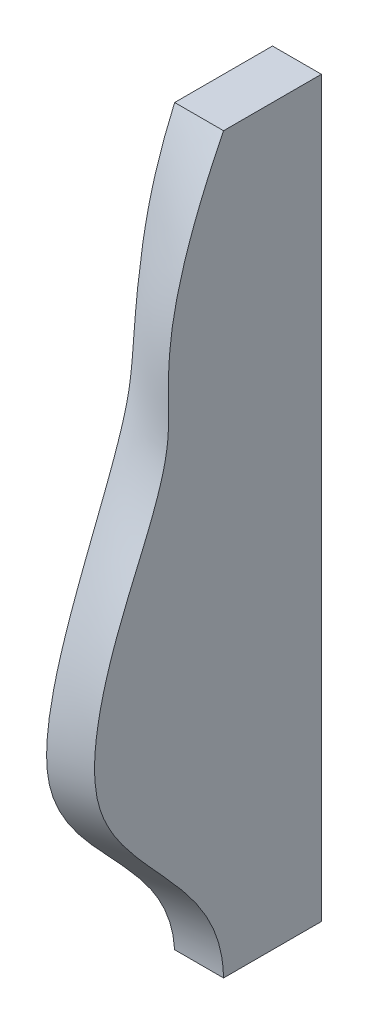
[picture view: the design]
ISO-10303-21;
HEADER;
FILE_DESCRIPTION(('STEP AP214'),'2;1');
FILE_NAME('part.step','',(''),(''),'','','');
FILE_SCHEMA(('AUTOMOTIVE_DESIGN { 1 0 10303 214 1 1 1 1 }'));
ENDSEC;
DATA;
#1=APPLICATION_CONTEXT('core data for automotive mechanical design processes');
#2=APPLICATION_PROTOCOL_DEFINITION('international standard','automotive_design',2000,#1);
#3=PRODUCT_CONTEXT('',#1,'mechanical');
#4=PRODUCT('Part','Part','',(#3));
#5=PRODUCT_RELATED_PRODUCT_CATEGORY('part','',(#4));
#6=PRODUCT_DEFINITION_FORMATION('','',#4);
#7=PRODUCT_DEFINITION_CONTEXT('part definition',#1,'design');
#8=PRODUCT_DEFINITION('design','',#6,#7);
#9=PRODUCT_DEFINITION_SHAPE('','',#8);
#10=(LENGTH_UNIT() NAMED_UNIT(*) SI_UNIT(.MILLI.,.METRE.));
#11=(NAMED_UNIT(*) PLANE_ANGLE_UNIT() SI_UNIT($,.RADIAN.));
#12=(NAMED_UNIT(*) SI_UNIT($,.STERADIAN.) SOLID_ANGLE_UNIT());
#13=UNCERTAINTY_MEASURE_WITH_UNIT(LENGTH_MEASURE(1.E-05),#10,'distance_accuracy_value','');
#14=(GEOMETRIC_REPRESENTATION_CONTEXT(3) GLOBAL_UNCERTAINTY_ASSIGNED_CONTEXT((#13)) GLOBAL_UNIT_ASSIGNED_CONTEXT((#10,
#11,#12)) REPRESENTATION_CONTEXT('',''));
#15=CARTESIAN_POINT('',(0.,0.,0.));
#16=DIRECTION('',(0.,0.,1.));
#17=DIRECTION('',(1.,0.,0.));
#18=AXIS2_PLACEMENT_3D('',#15,#16,#17);
#19=CARTESIAN_POINT('',(49.9999999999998,375.,253.120113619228));
#20=DIRECTION('',(1.,0.,0.));
#21=DIRECTION('',(0.,0.,-1.));
#22=AXIS2_PLACEMENT_3D('',#19,#20,#21);
#23=PLANE('',#22);
#24=CARTESIAN_POINT('',(49.9999999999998,375.,100.));
#25=CARTESIAN_POINT('',(49.9999999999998,373.168622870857,100.916189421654));
#26=CARTESIAN_POINT('',(49.9999999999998,371.334089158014,101.826077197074));
#27=CARTESIAN_POINT('',(49.9999999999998,367.660247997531,103.631973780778));
#28=CARTESIAN_POINT('',(49.9999999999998,365.820946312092,104.527994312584));
#29=CARTESIAN_POINT('',(49.9999999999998,362.137168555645,106.305876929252));
#30=CARTESIAN_POINT('',(49.9999999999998,360.292697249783,107.187748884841));
#31=CARTESIAN_POINT('',(49.9999999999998,356.598172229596,108.937033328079));
#32=CARTESIAN_POINT('',(49.9999999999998,354.748122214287,109.804453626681));
#33=CARTESIAN_POINT('',(49.9999999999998,351.042022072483,111.524514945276));
#34=CARTESIAN_POINT('',(49.9999999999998,349.185974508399,112.377161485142));
#35=CARTESIAN_POINT('',(49.9999999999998,345.467450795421,114.067332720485));
#36=CARTESIAN_POINT('',(49.9999999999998,343.604975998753,114.90486039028));
#37=CARTESIAN_POINT('',(49.9999999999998,339.897581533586,116.553563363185));
#38=CARTESIAN_POINT('',(49.9999999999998,338.052751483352,117.364940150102));
#39=CARTESIAN_POINT('',(49.9999999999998,334.35598507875,118.972212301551));
#40=CARTESIAN_POINT('',(49.9999999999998,332.504047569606,119.768105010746));
#41=CARTESIAN_POINT('',(49.9999999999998,328.792640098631,121.343978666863));
#42=CARTESIAN_POINT('',(49.9999999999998,326.933167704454,122.123953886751));
#43=CARTESIAN_POINT('',(49.9999999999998,323.206246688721,123.667520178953));
#44=CARTESIAN_POINT('',(49.9999999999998,321.338794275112,124.431102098));
#45=CARTESIAN_POINT('',(49.9999999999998,317.595448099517,125.941358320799));
#46=CARTESIAN_POINT('',(49.9999999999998,315.719549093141,126.68801962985));
#47=CARTESIAN_POINT('',(49.9999999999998,311.958818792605,128.163848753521));
#48=CARTESIAN_POINT('',(49.9999999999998,310.073980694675,128.892999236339));
#49=CARTESIAN_POINT('',(49.9999999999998,306.265596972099,130.34429258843));
#50=CARTESIAN_POINT('',(49.9999999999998,304.341929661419,131.066116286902));
#51=CARTESIAN_POINT('',(49.9999999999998,300.487016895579,132.489233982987));
#52=CARTESIAN_POINT('',(49.9999999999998,298.555771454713,133.190528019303));
#53=CARTESIAN_POINT('',(49.9999999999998,294.68424987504,134.572072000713));
#54=CARTESIAN_POINT('',(49.9999999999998,292.743968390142,135.252306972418));
#55=CARTESIAN_POINT('',(49.9999999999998,288.855617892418,136.590091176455));
#56=CARTESIAN_POINT('',(49.9999999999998,286.907548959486,137.247640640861));
#57=CARTESIAN_POINT('',(49.9999999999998,283.004365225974,138.538494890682));
#58=CARTESIAN_POINT('',(49.9999999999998,281.049254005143,139.171810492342));
#59=CARTESIAN_POINT('',(49.9999999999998,277.130982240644,140.413056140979));
#60=CARTESIAN_POINT('',(49.9999999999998,275.167821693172,141.020986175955));
#61=CARTESIAN_POINT('',(49.9999999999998,271.236123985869,142.208965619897));
#62=CARTESIAN_POINT('',(49.9999999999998,269.267598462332,142.789053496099));
#63=CARTESIAN_POINT('',(49.9999999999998,265.322260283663,143.920345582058));
#64=CARTESIAN_POINT('',(49.9999999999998,263.345447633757,144.471549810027));
#65=CARTESIAN_POINT('',(49.9999999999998,259.387696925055,145.542028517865));
#66=CARTESIAN_POINT('',(49.9999999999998,257.406776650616,146.061368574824));
#67=CARTESIAN_POINT('',(49.9999999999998,253.43672394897,147.067501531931));
#68=CARTESIAN_POINT('',(49.9999999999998,251.447591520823,147.554294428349));
#69=CARTESIAN_POINT('',(49.9999999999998,245.477945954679,148.960509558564));
#70=CARTESIAN_POINT('',(49.9999999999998,241.485046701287,149.828529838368));
#71=CARTESIAN_POINT('',(49.9999999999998,236.124367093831,150.88686863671));
#72=CARTESIAN_POINT('',(49.9999999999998,234.769759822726,151.145219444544));
#73=CARTESIAN_POINT('',(49.9999999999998,232.057202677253,151.643861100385));
#74=CARTESIAN_POINT('',(49.9999999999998,230.699252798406,151.884151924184));
#75=CARTESIAN_POINT('',(49.9999999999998,227.980192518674,152.346116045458));
#76=CARTESIAN_POINT('',(49.9999999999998,226.619082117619,152.567789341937));
#77=CARTESIAN_POINT('',(49.9999999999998,223.893831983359,152.992033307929));
#78=CARTESIAN_POINT('',(49.9999999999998,222.529692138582,153.194603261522));
#79=CARTESIAN_POINT('',(49.9999999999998,219.798652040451,153.580213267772));
#80=CARTESIAN_POINT('',(49.9999999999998,218.431751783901,153.763253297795));
#81=CARTESIAN_POINT('',(49.9999999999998,215.695441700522,154.109488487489));
#82=CARTESIAN_POINT('',(49.9999999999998,214.326031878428,154.272683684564));
#83=CARTESIAN_POINT('',(49.9999999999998,211.583465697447,154.579216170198));
#84=CARTESIAN_POINT('',(49.9999999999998,210.210306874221,154.72253141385));
#85=CARTESIAN_POINT('',(49.9999999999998,207.462038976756,154.989075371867));
#86=CARTESIAN_POINT('',(49.9999999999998,206.086929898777,155.112304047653));
#87=CARTESIAN_POINT('',(49.9999999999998,203.335080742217,155.338860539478));
#88=CARTESIAN_POINT('',(49.9999999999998,201.958340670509,155.44218843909));
#89=CARTESIAN_POINT('',(49.9999999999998,199.200402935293,155.629584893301));
#90=CARTESIAN_POINT('',(49.9999999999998,197.819202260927,155.713609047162));
#91=CARTESIAN_POINT('',(49.9999999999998,195.055784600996,155.862810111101));
#92=CARTESIAN_POINT('',(49.9999999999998,193.673567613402,155.927986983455));
#93=CARTESIAN_POINT('',(49.9999999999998,190.908421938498,156.040530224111));
#94=CARTESIAN_POINT('',(49.9999999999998,189.525493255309,156.087896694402));
#95=CARTESIAN_POINT('',(49.9999999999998,186.755163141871,156.166330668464));
#96=CARTESIAN_POINT('',(49.9999999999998,185.36776037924,156.197350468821));
#97=CARTESIAN_POINT('',(49.9999999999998,182.592709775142,156.244687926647));
#98=CARTESIAN_POINT('',(49.9999999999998,181.20506193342,156.261005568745));
#99=CARTESIAN_POINT('',(49.9999999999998,178.42968430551,156.281166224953));
#100=CARTESIAN_POINT('',(49.9999999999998,177.041954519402,156.285009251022));
#101=CARTESIAN_POINT('',(49.9999999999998,174.263514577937,156.282881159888));
#102=CARTESIAN_POINT('',(49.9999999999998,172.872804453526,156.276888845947));
#103=CARTESIAN_POINT('',(49.9999999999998,170.091440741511,156.258168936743));
#104=CARTESIAN_POINT('',(49.9999999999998,168.700787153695,156.24544136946));
#105=CARTESIAN_POINT('',(49.9999999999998,165.919509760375,156.21679163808));
#106=CARTESIAN_POINT('',(49.9999999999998,164.528885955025,156.200869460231));
#107=CARTESIAN_POINT('',(49.9999999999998,161.828743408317,156.170666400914));
#108=CARTESIAN_POINT('',(49.9999999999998,160.519225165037,156.156343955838));
#109=CARTESIAN_POINT('',(49.9999999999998,157.900148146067,156.131896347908));
#110=CARTESIAN_POINT('',(49.9999999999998,156.590589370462,156.121771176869));
#111=CARTESIAN_POINT('',(49.9999999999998,153.973399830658,156.109467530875));
#112=CARTESIAN_POINT('',(49.9999999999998,152.665769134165,156.107277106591));
#113=CARTESIAN_POINT('',(49.9999999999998,150.050521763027,156.114651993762));
#114=CARTESIAN_POINT('',(49.9999999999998,148.742905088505,156.124217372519));
#115=CARTESIAN_POINT('',(49.9999999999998,146.131329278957,156.158925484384));
#116=CARTESIAN_POINT('',(49.9999999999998,144.827369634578,156.184026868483));
#117=CARTESIAN_POINT('',(49.9999999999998,142.219976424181,156.25352767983));
#118=CARTESIAN_POINT('',(49.9999999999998,140.916542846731,156.297926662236));
#119=CARTESIAN_POINT('',(49.9999999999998,138.31452137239,156.40942306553));
#120=CARTESIAN_POINT('',(49.9999999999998,137.015930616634,156.476452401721));
#121=CARTESIAN_POINT('',(49.9999999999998,134.420329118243,156.636476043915));
#122=CARTESIAN_POINT('',(49.9999999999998,133.123318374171,156.729470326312));
#123=CARTESIAN_POINT('',(49.9999999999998,130.534621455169,156.944010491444));
#124=CARTESIAN_POINT('',(49.9999999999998,129.242929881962,157.065490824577));
#125=CARTESIAN_POINT('',(49.9999999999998,126.662804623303,157.339454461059));
#126=CARTESIAN_POINT('',(49.9999999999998,125.374370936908,157.491937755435));
#127=CARTESIAN_POINT('',(49.9999999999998,123.445367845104,157.745182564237));
#128=CARTESIAN_POINT('',(49.9999999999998,122.803166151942,157.833654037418));
#129=CARTESIAN_POINT('',(49.9999999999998,121.519964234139,158.018944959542));
#130=CARTESIAN_POINT('',(49.9999999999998,120.87896400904,158.115764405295));
#131=CARTESIAN_POINT('',(49.9999999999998,119.598308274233,158.317869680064));
#132=CARTESIAN_POINT('',(49.9999999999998,118.958652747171,158.423155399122));
#133=CARTESIAN_POINT('',(49.9999999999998,117.6808213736,158.642348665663));
#134=CARTESIAN_POINT('',(49.9999999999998,117.04264552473,158.756256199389));
#135=CARTESIAN_POINT('',(49.9999999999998,115.775918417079,158.990984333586));
#136=CARTESIAN_POINT('',(49.9999999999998,115.14734755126,159.111699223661));
#137=CARTESIAN_POINT('',(49.9999999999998,113.891729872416,159.360796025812));
#138=CARTESIAN_POINT('',(49.9999999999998,113.26468306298,159.489177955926));
#139=CARTESIAN_POINT('',(49.9999999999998,111.385815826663,159.88518825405));
#140=CARTESIAN_POINT('',(49.9999999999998,110.136273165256,160.163680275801));
#141=CARTESIAN_POINT('',(49.9999999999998,107.639083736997,160.747441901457));
#142=CARTESIAN_POINT('',(49.9999999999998,106.391457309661,161.052798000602));
#143=CARTESIAN_POINT('',(49.9999999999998,103.902144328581,161.686736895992));
#144=CARTESIAN_POINT('',(49.9999999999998,102.660457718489,162.015319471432));
#145=CARTESIAN_POINT('',(49.9999999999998,100.178746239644,162.694390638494));
#146=CARTESIAN_POINT('',(49.9999999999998,98.9387400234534,163.044947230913));
#147=CARTESIAN_POINT('',(49.9999999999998,96.4641822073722,163.764818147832));
#148=CARTESIAN_POINT('',(49.9999999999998,95.2296306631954,164.134132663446));
#149=CARTESIAN_POINT('',(49.9999999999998,92.7627115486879,164.890465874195));
#150=CARTESIAN_POINT('',(49.9999999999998,91.5303564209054,165.277525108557));
#151=CARTESIAN_POINT('',(49.9999999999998,89.6854616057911,165.869410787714));
#152=CARTESIAN_POINT('',(49.9999999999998,89.0711023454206,166.068589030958));
#153=CARTESIAN_POINT('',(49.9999999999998,87.8435498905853,166.470513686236));
#154=CARTESIAN_POINT('',(49.9999999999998,87.2303566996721,166.673260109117));
#155=CARTESIAN_POINT('',(49.9999999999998,85.391128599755,167.287129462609));
#156=CARTESIAN_POINT('',(49.9999999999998,84.1668215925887,167.703440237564));
#157=CARTESIAN_POINT('',(49.9999999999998,81.7226474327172,168.548864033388));
#158=CARTESIAN_POINT('',(49.9999999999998,80.5027802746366,168.977977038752));
#159=CARTESIAN_POINT('',(49.9999999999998,76.8504835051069,170.282671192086));
#160=CARTESIAN_POINT('',(49.9999999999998,74.4243615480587,171.17594200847));
#161=CARTESIAN_POINT('',(49.9999999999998,69.0381510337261,173.208885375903));
#162=CARTESIAN_POINT('',(49.9999999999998,66.0818199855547,174.358475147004));
#163=CARTESIAN_POINT('',(49.9999999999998,60.1933884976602,176.700073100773));
#164=CARTESIAN_POINT('',(49.9999999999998,57.2612498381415,177.891985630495));
#165=CARTESIAN_POINT('',(49.9999999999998,51.4139279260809,180.305404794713));
#166=CARTESIAN_POINT('',(49.9999999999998,48.4987269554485,181.52686867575));
#167=CARTESIAN_POINT('',(49.9999999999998,42.6783163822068,183.987287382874));
#168=CARTESIAN_POINT('',(49.9999999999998,39.7731009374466,185.226228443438));
#169=CARTESIAN_POINT('',(49.9999999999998,33.9660268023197,187.710285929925));
#170=CARTESIAN_POINT('',(49.9999999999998,31.0641675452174,188.955401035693));
#171=CARTESIAN_POINT('',(49.9999999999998,25.2575418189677,191.44136635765));
#172=CARTESIAN_POINT('',(49.9999999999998,22.3527747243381,192.682215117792));
#173=CARTESIAN_POINT('',(49.9999999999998,16.5149479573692,195.158447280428));
#174=CARTESIAN_POINT('',(49.9999999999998,13.5818404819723,196.393718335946));
#175=CARTESIAN_POINT('',(49.9999999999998,7.70402843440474,198.840495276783));
#176=CARTESIAN_POINT('',(49.9999999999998,4.75931891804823,200.051989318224));
#177=CARTESIAN_POINT('',(49.9999999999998,-1.14397938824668,202.442508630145));
#178=CARTESIAN_POINT('',(49.9999999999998,-4.1025708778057,203.621527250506));
#179=CARTESIAN_POINT('',(49.9999999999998,-10.0355066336,205.93944408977));
#180=CARTESIAN_POINT('',(49.9999999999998,-13.0098510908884,207.078341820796));
#181=CARTESIAN_POINT('',(49.9999999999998,-18.9758242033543,209.309226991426));
#182=CARTESIAN_POINT('',(49.9999999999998,-21.9674513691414,210.401218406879));
#183=CARTESIAN_POINT('',(49.9999999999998,-27.9693221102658,212.532099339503));
#184=CARTESIAN_POINT('',(49.9999999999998,-30.979564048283,213.570993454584));
#185=CARTESIAN_POINT('',(49.9999999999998,-36.0653742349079,215.270721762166));
#186=CARTESIAN_POINT('',(49.9999999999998,-38.1356947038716,215.947279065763));
#187=CARTESIAN_POINT('',(49.9999999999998,-42.2858388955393,217.270784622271));
#188=CARTESIAN_POINT('',(49.9999999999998,-44.3656628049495,217.917732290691));
#189=CARTESIAN_POINT('',(49.9999999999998,-48.5349723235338,219.179935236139));
#190=CARTESIAN_POINT('',(49.9999999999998,-50.6244581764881,219.795189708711));
#191=CARTESIAN_POINT('',(49.9999999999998,-54.8132928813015,220.991807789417));
#192=CARTESIAN_POINT('',(49.9999999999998,-56.912642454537,221.573168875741));
#193=CARTESIAN_POINT('',(49.9999999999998,-61.1214608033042,222.699602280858));
#194=CARTESIAN_POINT('',(49.9999999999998,-63.2309312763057,223.244668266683));
#195=CARTESIAN_POINT('',(49.9999999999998,-67.4602944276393,224.29595287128));
#196=CARTESIAN_POINT('',(49.9999999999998,-69.5801903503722,224.802158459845));
#197=CARTESIAN_POINT('',(49.9999999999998,-73.8327991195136,225.773406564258));
#198=CARTESIAN_POINT('',(49.9999999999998,-75.9655265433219,226.238385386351));
#199=CARTESIAN_POINT('',(49.9999999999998,-80.2406312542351,227.123051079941));
#200=CARTESIAN_POINT('',(49.9999999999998,-82.3830096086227,227.5427328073));
#201=CARTESIAN_POINT('',(49.9999999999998,-86.6764922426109,228.33289399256));
#202=CARTESIAN_POINT('',(49.9999999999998,-88.8275950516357,228.703381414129));
#203=CARTESIAN_POINT('',(49.9999999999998,-93.1376707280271,229.390805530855));
#204=CARTESIAN_POINT('',(49.9999999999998,-95.2966408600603,229.707759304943));
#205=CARTESIAN_POINT('',(49.9999999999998,-99.6216858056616,230.28326610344));
#206=CARTESIAN_POINT('',(49.9999999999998,-101.787758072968,230.541838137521));
#207=CARTESIAN_POINT('',(49.9999999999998,-106.126304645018,230.995136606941));
#208=CARTESIAN_POINT('',(49.9999999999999,-108.298778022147,231.189871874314));
#209=CARTESIAN_POINT('',(49.9999999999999,-113.018153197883,231.536441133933));
#210=CARTESIAN_POINT('',(49.9999999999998,-115.566028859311,231.675385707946));
#211=CARTESIAN_POINT('',(49.9999999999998,-120.665522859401,231.846252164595));
#212=CARTESIAN_POINT('',(49.9999999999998,-123.217141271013,231.878171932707));
#213=CARTESIAN_POINT('',(49.9999999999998,-128.320374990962,231.822320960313));
#214=CARTESIAN_POINT('',(49.9999999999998,-130.871989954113,231.734506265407));
#215=CARTESIAN_POINT('',(49.9999999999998,-134.683776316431,231.503089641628));
#216=CARTESIAN_POINT('',(49.9999999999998,-135.947128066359,231.4098607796));
#217=CARTESIAN_POINT('',(49.9999999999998,-138.470823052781,231.188656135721));
#218=CARTESIAN_POINT('',(49.9999999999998,-139.731166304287,231.060680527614));
#219=CARTESIAN_POINT('',(49.9999999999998,-142.247325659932,230.768183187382));
#220=CARTESIAN_POINT('',(49.9999999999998,-143.503142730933,230.603669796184));
#221=CARTESIAN_POINT('',(49.9999999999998,-146.009186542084,230.236221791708));
#222=CARTESIAN_POINT('',(49.9999999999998,-147.259413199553,230.033286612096));
#223=CARTESIAN_POINT('',(49.9999999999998,-149.751779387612,229.587308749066));
#224=CARTESIAN_POINT('',(49.9999999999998,-150.993924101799,229.344295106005));
#225=CARTESIAN_POINT('',(49.9999999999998,-153.46923676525,228.816286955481));
#226=CARTESIAN_POINT('',(49.9999999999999,-154.702405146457,228.531294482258));
#227=CARTESIAN_POINT('',(49.9999999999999,-156.859555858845,227.992105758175));
#228=CARTESIAN_POINT('',(49.9999999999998,-157.785878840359,227.747244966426));
#229=CARTESIAN_POINT('',(49.9999999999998,-159.63136596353,227.231930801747));
#230=CARTESIAN_POINT('',(49.9999999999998,-160.550530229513,226.961477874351));
#231=CARTESIAN_POINT('',(49.9999999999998,-162.381710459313,226.395978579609));
#232=CARTESIAN_POINT('',(49.9999999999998,-163.29372300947,226.100921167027));
#233=CARTESIAN_POINT('',(49.9999999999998,-165.109815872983,225.48739345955));
#234=CARTESIAN_POINT('',(49.9999999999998,-166.013896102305,225.168922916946));
#235=CARTESIAN_POINT('',(49.9999999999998,-168.714789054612,224.179813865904));
#236=CARTESIAN_POINT('',(49.9999999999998,-170.49948130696,223.475718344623));
#237=CARTESIAN_POINT('',(49.9999999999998,-173.151073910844,222.359994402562));
#238=CARTESIAN_POINT('',(49.9999999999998,-174.030711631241,221.978149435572));
#239=CARTESIAN_POINT('',(49.9999999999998,-175.781441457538,221.195340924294));
#240=CARTESIAN_POINT('',(49.9999999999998,-176.652533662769,220.794377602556));
#241=CARTESIAN_POINT('',(49.9999999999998,-179.262726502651,219.559411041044));
#242=CARTESIAN_POINT('',(49.9999999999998,-180.988721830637,218.697564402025));
#243=CARTESIAN_POINT('',(49.9999999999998,-184.404889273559,216.907236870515));
#244=CARTESIAN_POINT('',(49.9999999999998,-186.095073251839,215.978778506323));
#245=CARTESIAN_POINT('',(49.9999999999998,-189.440774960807,214.061839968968));
#246=CARTESIAN_POINT('',(49.9999999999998,-191.096296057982,213.073365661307));
#247=CARTESIAN_POINT('',(49.9999999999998,-194.373725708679,211.043106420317));
#248=CARTESIAN_POINT('',(49.9999999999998,-195.995641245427,210.001332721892));
#249=CARTESIAN_POINT('',(49.9999999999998,-200.096317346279,207.281278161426));
#250=CARTESIAN_POINT('',(49.9999999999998,-202.552934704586,205.569582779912));
#251=CARTESIAN_POINT('',(49.9999999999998,-207.399173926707,202.053335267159));
#252=CARTESIAN_POINT('',(49.9999999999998,-209.788780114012,200.24876168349));
#253=CARTESIAN_POINT('',(49.9999999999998,-214.512226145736,196.564799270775));
#254=CARTESIAN_POINT('',(49.9999999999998,-216.846023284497,194.685355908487));
#255=CARTESIAN_POINT('',(49.9999999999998,-221.468134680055,190.868808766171));
#256=CARTESIAN_POINT('',(49.9999999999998,-223.756420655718,188.931670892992));
#257=CARTESIAN_POINT('',(49.9999999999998,-228.297193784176,185.016084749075));
#258=CARTESIAN_POINT('',(49.9999999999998,-230.549681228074,183.037636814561));
#259=CARTESIAN_POINT('',(49.9999999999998,-235.038702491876,179.045647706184));
#260=CARTESIAN_POINT('',(49.9999999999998,-237.275142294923,177.032001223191));
#261=CARTESIAN_POINT('',(49.9999999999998,-241.733252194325,172.991316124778));
#262=CARTESIAN_POINT('',(49.9999999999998,-243.954930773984,170.964286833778));
#263=CARTESIAN_POINT('',(49.9999999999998,-248.395313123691,166.908752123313));
#264=CARTESIAN_POINT('',(49.9999999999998,-250.614017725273,164.880247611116));
#265=CARTESIAN_POINT('',(49.9999999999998,-255.060044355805,160.83346026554));
#266=CARTESIAN_POINT('',(49.9999999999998,-257.287364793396,158.81517568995));
#267=CARTESIAN_POINT('',(49.9999999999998,-261.762214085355,154.800515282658));
#268=CARTESIAN_POINT('',(49.9999999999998,-264.009745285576,152.804142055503));
#269=CARTESIAN_POINT('',(49.9999999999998,-268.390873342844,148.972801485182));
#270=CARTESIAN_POINT('',(49.9999999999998,-270.522573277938,147.135672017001));
#271=CARTESIAN_POINT('',(49.9999999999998,-274.821761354,143.502868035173));
#272=CARTESIAN_POINT('',(49.9999999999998,-276.989255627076,141.707200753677));
#273=CARTESIAN_POINT('',(49.9999999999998,-281.36809217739,138.169427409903));
#274=CARTESIAN_POINT('',(49.9999999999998,-283.579439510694,136.427327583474));
#275=CARTESIAN_POINT('',(49.9999999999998,-288.054312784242,133.009129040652));
#276=CARTESIAN_POINT('',(49.9999999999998,-290.31786149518,131.333060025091));
#277=CARTESIAN_POINT('',(49.9999999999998,-294.890488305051,128.070674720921));
#278=CARTESIAN_POINT('',(49.9999999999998,-297.199253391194,126.483921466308));
#279=CARTESIAN_POINT('',(49.9999999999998,-301.879446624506,123.405292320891));
#280=CARTESIAN_POINT('',(49.9999999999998,-304.25087576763,121.913417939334));
#281=CARTESIAN_POINT('',(49.9999999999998,-309.058843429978,119.040960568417));
#282=CARTESIAN_POINT('',(49.9999999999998,-311.495344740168,117.660315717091));
#283=CARTESIAN_POINT('',(49.9999999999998,-315.20008407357,115.684528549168));
#284=CARTESIAN_POINT('',(49.9999999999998,-316.443133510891,115.041887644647));
#285=CARTESIAN_POINT('',(49.9999999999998,-318.945994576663,113.790159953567));
#286=CARTESIAN_POINT('',(49.9999999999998,-320.205805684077,113.181072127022));
#287=CARTESIAN_POINT('',(49.9999999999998,-323.163909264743,111.801611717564));
#288=CARTESIAN_POINT('',(49.9999999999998,-324.868644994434,111.044994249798));
#289=CARTESIAN_POINT('',(49.9999999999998,-328.306598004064,109.599025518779));
#290=CARTESIAN_POINT('',(49.9999999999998,-330.039817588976,108.90967973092));
#291=CARTESIAN_POINT('',(49.9999999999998,-333.532971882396,107.602243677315));
#292=CARTESIAN_POINT('',(49.9999999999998,-335.292906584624,106.984153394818));
#293=CARTESIAN_POINT('',(49.9999999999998,-338.837449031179,105.822577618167));
#294=CARTESIAN_POINT('',(49.9999999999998,-340.62205918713,105.279099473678));
#295=CARTESIAN_POINT('',(49.9999999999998,-344.21159607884,104.269980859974));
#296=CARTESIAN_POINT('',(49.9999999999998,-346.01650498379,103.80427702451));
#297=CARTESIAN_POINT('',(49.9999999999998,-349.645061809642,102.952127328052));
#298=CARTESIAN_POINT('',(49.9999999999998,-351.468710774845,102.565685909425));
#299=CARTESIAN_POINT('',(49.9999999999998,-355.13073863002,101.873343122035));
#300=CARTESIAN_POINT('',(49.9999999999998,-356.969113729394,101.567421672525));
#301=CARTESIAN_POINT('',(49.9999999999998,-360.656549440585,101.036446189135));
#302=CARTESIAN_POINT('',(49.9999999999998,-362.505603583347,100.811347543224));
#303=CARTESIAN_POINT('',(49.9999999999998,-364.94837480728,100.567414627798));
#304=CARTESIAN_POINT('',(49.9999999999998,-365.538656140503,100.512569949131));
#305=CARTESIAN_POINT('',(49.9999999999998,-366.719818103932,100.410968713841));
#306=CARTESIAN_POINT('',(49.9999999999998,-367.310698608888,100.364210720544));
#307=CARTESIAN_POINT('',(49.9999999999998,-368.49298706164,100.27873728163));
#308=CARTESIAN_POINT('',(49.9999999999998,-369.084394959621,100.240021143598));
#309=CARTESIAN_POINT('',(49.9999999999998,-370.266986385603,100.170618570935));
#310=CARTESIAN_POINT('',(49.9999999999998,-370.858169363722,100.139922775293));
#311=CARTESIAN_POINT('',(49.9999999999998,-372.040942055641,100.086445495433));
#312=CARTESIAN_POINT('',(49.9999999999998,-372.632531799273,100.06366467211));
#313=CARTESIAN_POINT('',(49.9999999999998,-373.816057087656,100.025955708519));
#314=CARTESIAN_POINT('',(49.9999999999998,-374.407992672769,100.011028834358));
#315=CARTESIAN_POINT('',(49.9999999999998,-375.,100.));
#316=B_SPLINE_CURVE_WITH_KNOTS('',3,(#24,#25,#26,#27,#28,#29,#30,#31,#32,#33,#34,#35,#36,#37,
#38,#39,#40,#41,#42,#43,#44,#45,#46,#47,#48,#49,#50,#51,#52,#53,#54,#55,#56,#57,#58,#59,#60,#61,
#62,#63,#64,#65,#66,#67,#68,#69,#70,#71,#72,#73,#74,#75,#76,#77,#78,#79,#80,#81,#82,#83,#84,#85,
#86,#87,#88,#89,#90,#91,#92,#93,#94,#95,#96,#97,#98,#99,#100,#101,#102,#103,#104,#105,#106,#107,
#108,#109,#110,#111,#112,#113,#114,#115,#116,#117,#118,#119,#120,#121,#122,#123,#124,#125,#126,
#127,#128,#129,#130,#131,#132,#133,#134,#135,#136,#137,#138,#139,#140,#141,#142,#143,#144,#145,
#146,#147,#148,#149,#150,#151,#152,#153,#154,#155,#156,#157,#158,#159,#160,#161,#162,#163,#164,
#165,#166,#167,#168,#169,#170,#171,#172,#173,#174,#175,#176,#177,#178,#179,#180,#181,#182,#183,
#184,#185,#186,#187,#188,#189,#190,#191,#192,#193,#194,#195,#196,#197,#198,#199,#200,#201,#202,
#203,#204,#205,#206,#207,#208,#209,#210,#211,#212,#213,#214,#215,#216,#217,#218,#219,#220,#221,
#222,#223,#224,#225,#226,#227,#228,#229,#230,#231,#232,#233,#234,#235,#236,#237,#238,#239,#240,
#241,#242,#243,#244,#245,#246,#247,#248,#249,#250,#251,#252,#253,#254,#255,#256,#257,#258,#259,
#260,#261,#262,#263,#264,#265,#266,#267,#268,#269,#270,#271,#272,#273,#274,#275,#276,#277,#278,
#279,#280,#281,#282,#283,#284,#285,#286,#287,#288,#289,#290,#291,#292,#293,#294,#295,#296,#297,
#298,#299,#300,#301,#302,#303,#304,#305,#306,#307,#308,#309,#310,#311,#312,#313,#314,#315),
.UNSPECIFIED.,.F.,.F.,(4,2,2,2,2,2,2,2,2,2,2,2,2,2,2,2,2,2,2,2,2,2,2,2,2,2,2,2,2,2,2,2,2,2,2,2,
2,2,2,2,2,2,2,2,2,2,2,2,2,2,2,2,2,2,2,2,2,2,2,2,2,2,2,2,2,2,2,2,2,2,2,2,2,2,2,2,2,2,2,2,2,2,2,2,
2,2,2,2,2,2,2,2,2,2,2,2,2,2,2,2,2,2,2,2,2,2,2,2,2,2,2,2,2,2,2,2,2,2,2,2,2,2,2,2,2,2,2,2,2,2,2,2,
2,2,2,2,2,2,2,2,2,2,2,2,2,4),(0.,6.14329093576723,12.2810682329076,18.414358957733,
24.544219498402,30.6717380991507,36.7980378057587,42.8440886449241,48.8911673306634,
54.9403846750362,60.9928961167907,67.0499081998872,73.1126869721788,79.27648019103,
85.440261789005,91.6083297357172,97.7763345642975,103.94155354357,110.106775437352,
116.263218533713,122.419657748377,128.562969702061,134.706282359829,146.961400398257,
151.098395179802,155.235395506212,159.372396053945,163.5095515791,167.646711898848,
171.783864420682,175.925568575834,180.067280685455,184.208975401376,188.360103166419,
192.511239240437,196.662351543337,200.825511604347,204.988676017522,209.151836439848,
213.323980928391,217.496108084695,221.668253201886,225.597041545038,229.525822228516,
233.448683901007,237.371568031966,241.284056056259,245.196453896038,249.097184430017,
252.997911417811,256.88974898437,260.781585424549,262.72634128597,264.671096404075,
266.615826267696,268.56055302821,270.480672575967,272.400796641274,276.241058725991,
280.094172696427,283.947250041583,287.81290386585,291.678597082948,295.553610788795,
297.491121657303,299.428638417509,303.308008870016,307.187374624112,314.94295168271,
324.458392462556,333.95354802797,343.435703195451,352.910766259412,362.383883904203,
371.859965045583,381.407728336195,390.960132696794,400.514478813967,410.068941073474,
419.622591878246,429.175413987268,435.709406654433,442.243528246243,448.777815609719,
455.312588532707,461.848498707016,468.386590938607,474.9346143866,481.483380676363,
488.031085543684,494.576697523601,501.120175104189,507.662746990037,515.315657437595,
522.968719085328,530.624590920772,534.424558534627,538.224507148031,542.023589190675,
545.822727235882,549.619124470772,553.415337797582,556.289408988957,559.163430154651,
562.038748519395,564.914097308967,570.667220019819,573.543877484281,576.420501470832,
582.206358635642,587.990268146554,593.773613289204,599.555744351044,608.535283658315,
617.516906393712,626.505195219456,635.498905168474,644.492541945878,653.520589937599,
662.54290032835,671.561623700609,680.578754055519,689.596944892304,698.038863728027,
706.482244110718,714.926603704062,723.374719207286,731.777076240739,740.17956689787,
748.577351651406,752.774953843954,756.972425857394,762.566311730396,768.160652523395,
773.754992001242,779.349882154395,784.940191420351,790.530813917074,796.120040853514,
801.70617792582,803.484616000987,805.262737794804,807.040706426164,808.81659052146,
810.592622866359,812.368941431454),.UNSPECIFIED.);
#317=CARTESIAN_POINT('',(49.9999999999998,375.,100.));
#318=VERTEX_POINT('',#317);
#319=CARTESIAN_POINT('',(49.9999999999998,-375.,100.));
#320=VERTEX_POINT('',#319);
#321=EDGE_CURVE('E88',#318,#320,#316,.T.);
#322=ORIENTED_EDGE('',*,*,#321,.T.);
#323=DIRECTION('',(0.,0.,-1.));
#324=VECTOR('',#323,1.);
#325=CARTESIAN_POINT('',(49.9999999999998,-375.,253.120113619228));
#326=LINE('',#325,#324);
#327=CARTESIAN_POINT('',(49.9999999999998,-375.,0.));
#328=VERTEX_POINT('',#327);
#329=EDGE_CURVE('E50',#320,#328,#326,.T.);
#330=ORIENTED_EDGE('',*,*,#329,.T.);
#331=DIRECTION('',(0.,-1.,0.));
#332=VECTOR('',#331,1.);
#333=CARTESIAN_POINT('',(49.9999999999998,375.,0.));
#334=LINE('',#333,#332);
#335=CARTESIAN_POINT('',(49.9999999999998,375.,0.));
#336=VERTEX_POINT('',#335);
#337=EDGE_CURVE('E87',#336,#328,#334,.T.);
#338=ORIENTED_EDGE('',*,*,#337,.F.);
#339=DIRECTION('',(0.,0.,-1.));
#340=VECTOR('',#339,1.);
#341=CARTESIAN_POINT('',(49.9999999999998,375.,253.120113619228));
#342=LINE('',#341,#340);
#343=EDGE_CURVE('E65',#318,#336,#342,.T.);
#344=ORIENTED_EDGE('',*,*,#343,.F.);
#345=EDGE_LOOP('',(#322,#330,#338,#344));
#346=FACE_BOUND('',#345,.T.);
#347=ADVANCED_FACE('F35',(#346),#23,.T.);
#348=CARTESIAN_POINT('',(0.,0.,0.));
#349=DIRECTION('',(0.,0.,-1.));
#350=DIRECTION('',(-1.,0.,0.));
#351=AXIS2_PLACEMENT_3D('',#348,#349,#350);
#352=PLANE('',#351);
#353=DIRECTION('',(1.,0.,0.));
#354=VECTOR('',#353,1.);
#355=CARTESIAN_POINT('',(-750.,-375.,0.));
#356=LINE('',#355,#354);
#357=CARTESIAN_POINT('',(0.,-375.,0.));
#358=VERTEX_POINT('',#357);
#359=EDGE_CURVE('E79',#358,#328,#356,.T.);
#360=ORIENTED_EDGE('',*,*,#359,.F.);
#361=DIRECTION('',(0.,1.,0.));
#362=VECTOR('',#361,1.);
#363=CARTESIAN_POINT('',(-1.11022302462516E-13,375.,0.));
#364=LINE('',#363,#362);
#365=CARTESIAN_POINT('',(-1.11022302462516E-13,375.,0.));
#366=VERTEX_POINT('',#365);
#367=EDGE_CURVE('E157',#358,#366,#364,.T.);
#368=ORIENTED_EDGE('',*,*,#367,.T.);
#369=DIRECTION('',(-1.,0.,0.));
#370=VECTOR('',#369,1.);
#371=CARTESIAN_POINT('',(-750.,375.,0.));
#372=LINE('',#371,#370);
#373=EDGE_CURVE('E93',#336,#366,#372,.T.);
#374=ORIENTED_EDGE('',*,*,#373,.F.);
#375=ORIENTED_EDGE('',*,*,#337,.T.);
#376=EDGE_LOOP('',(#360,#368,#374,#375));
#377=FACE_BOUND('',#376,.T.);
#378=ADVANCED_FACE('F91',(#377),#352,.T.);
#379=CARTESIAN_POINT('',(750.,-375.,100.));
#380=CARTESIAN_POINT('',(750.,-302.078506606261,100.));
#381=CARTESIAN_POINT('',(750.,-224.483786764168,100.));
#382=CARTESIAN_POINT('',(750.,-61.5160152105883,100.));
#383=CARTESIAN_POINT('',(750.,39.4445673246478,100.));
#384=CARTESIAN_POINT('',(750.,211.849847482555,100.));
#385=CARTESIAN_POINT('',(750.,298.882075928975,100.));
#386=CARTESIAN_POINT('',(750.,375.,100.));
#387=CARTESIAN_POINT('',(669.085175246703,-375.,100.));
#388=CARTESIAN_POINT('',(669.085175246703,-302.078506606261,100.));
#389=CARTESIAN_POINT('',(669.085175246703,-234.282472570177,121.198481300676));
#390=CARTESIAN_POINT('',(669.085175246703,-62.2283080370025,120.288550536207));
#391=CARTESIAN_POINT('',(669.085175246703,68.0647781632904,82.7868169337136));
#392=CARTESIAN_POINT('',(669.085175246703,240.312514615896,73.0426687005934));
#393=CARTESIAN_POINT('',(669.085175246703,298.882075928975,100.));
#394=CARTESIAN_POINT('',(669.085175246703,375.,100.));
#395=CARTESIAN_POINT('',(500.445116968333,-375.,100.));
#396=CARTESIAN_POINT('',(517.991528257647,-284.627602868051,95.5040591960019));
#397=CARTESIAN_POINT('',(530.038001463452,-221.673003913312,150.719602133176));
#398=CARTESIAN_POINT('',(473.74510655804,-71.7416270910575,167.060530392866));
#399=CARTESIAN_POINT('',(387.213321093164,45.6135081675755,91.591323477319));
#400=CARTESIAN_POINT('',(378.694107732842,207.638743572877,66.6461848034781));
#401=CARTESIAN_POINT('',(433.17831170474,253.396603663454,122.492891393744));
#402=CARTESIAN_POINT('',(500.445116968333,375.,100.));
#403=CARTESIAN_POINT('',(285.091607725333,-375.,100.));
#404=CARTESIAN_POINT('',(309.270321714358,-264.297524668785,86.4064578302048));
#405=CARTESIAN_POINT('',(325.856840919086,-200.08226970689,164.07204721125));
#406=CARTESIAN_POINT('',(247.47112957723,-80.9425320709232,234.992870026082));
#407=CARTESIAN_POINT('',(127.240382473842,2.40271344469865,186.756001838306));
#408=CARTESIAN_POINT('',(115.567806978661,152.518027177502,151.057444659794));
#409=CARTESIAN_POINT('',(191.428893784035,202.025100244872,189.039851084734));
#410=CARTESIAN_POINT('',(285.091607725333,375.,100.));
#411=CARTESIAN_POINT('',(47.4554331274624,-375.,100.));
#412=CARTESIAN_POINT('',(51.0669239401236,-278.639867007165,99.5141662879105));
#413=CARTESIAN_POINT('',(52.9210710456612,-231.452124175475,201.325948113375));
#414=CARTESIAN_POINT('',(3.18149891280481,-90.8615864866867,272.445475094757));
#415=CARTESIAN_POINT('',(-61.0346058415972,45.7948958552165,186.157760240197));
#416=CARTESIAN_POINT('',(-59.6612105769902,205.286893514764,133.941969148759));
#417=CARTESIAN_POINT('',(-11.8049718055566,220.40073671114,189.8209162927));
#418=CARTESIAN_POINT('',(47.4554331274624,375.,100.));
#419=CARTESIAN_POINT('',(-175.903454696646,-375.,100.));
#420=CARTESIAN_POINT('',(-199.823715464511,-320.588060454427,126.731848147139));
#421=CARTESIAN_POINT('',(-216.967937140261,-300.821135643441,242.921959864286));
#422=CARTESIAN_POINT('',(-184.265304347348,-55.1410097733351,206.147478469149));
#423=CARTESIAN_POINT('',(-119.865061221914,249.096629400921,-32.5779079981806));
#424=CARTESIAN_POINT('',(-104.641938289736,431.262460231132,-94.4845569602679));
#425=CARTESIAN_POINT('',(-136.623034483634,348.137040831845,60.785640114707));
#426=CARTESIAN_POINT('',(-175.903454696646,375.,100.));
#427=CARTESIAN_POINT('',(-355.235514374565,-375.,100.));
#428=CARTESIAN_POINT('',(-319.200833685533,-282.590755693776,58.2859511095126));
#429=CARTESIAN_POINT('',(-293.075279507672,-226.888141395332,104.97090627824));
#430=CARTESIAN_POINT('',(-324.119079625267,-68.6572837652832,122.102733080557));
#431=CARTESIAN_POINT('',(-398.972481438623,73.039345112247,53.3701087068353));
#432=CARTESIAN_POINT('',(-423.398679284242,233.384819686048,47.4380317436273));
#433=CARTESIAN_POINT('',(-392.720188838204,253.575952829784,124.952096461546));
#434=CARTESIAN_POINT('',(-355.235514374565,375.,100.));
#435=CARTESIAN_POINT('',(-536.684515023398,-375.,100.));
#436=CARTESIAN_POINT('',(-494.827225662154,-277.129657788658,52.0422385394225));
#437=CARTESIAN_POINT('',(-464.573647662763,-205.017596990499,67.039018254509));
#438=CARTESIAN_POINT('',(-506.334367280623,-72.2467511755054,96.5036749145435));
#439=CARTESIAN_POINT('',(-600.216684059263,9.35641022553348,95.9941925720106));
#440=CARTESIAN_POINT('',(-628.122542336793,166.946160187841,106.349064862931));
#441=CARTESIAN_POINT('',(-587.011939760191,237.095914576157,138.331902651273));
#442=CARTESIAN_POINT('',(-536.684515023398,375.,100.));
#443=CARTESIAN_POINT('',(-644.685568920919,-375.,100.));
#444=CARTESIAN_POINT('',(-644.685568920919,-302.078506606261,100.));
#445=CARTESIAN_POINT('',(-644.685568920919,-237.237234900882,127.59081546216));
#446=CARTESIAN_POINT('',(-644.685568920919,-62.4430976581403,126.406497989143));
#447=CARTESIAN_POINT('',(-644.685568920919,76.6951111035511,77.5962366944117));
#448=CARTESIAN_POINT('',(-644.685568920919,248.895340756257,64.9137717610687));
#449=CARTESIAN_POINT('',(-644.685568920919,298.882075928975,100.));
#450=CARTESIAN_POINT('',(-644.685568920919,375.,100.));
#451=CARTESIAN_POINT('',(-750.,-375.,100.));
#452=CARTESIAN_POINT('',(-750.,-302.078506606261,100.));
#453=CARTESIAN_POINT('',(-750.,-224.483786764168,100.));
#454=CARTESIAN_POINT('',(-750.,-61.5160152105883,100.));
#455=CARTESIAN_POINT('',(-750.,39.4445673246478,100.));
#456=CARTESIAN_POINT('',(-750.,211.849847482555,100.));
#457=CARTESIAN_POINT('',(-750.,298.882075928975,100.));
#458=CARTESIAN_POINT('',(-750.,375.,100.));
#459=B_SPLINE_SURFACE_WITH_KNOTS('',3,3,((#379,#380,#381,#382,#383,#384,#385,#386),(#387,#388,
#389,#390,#391,#392,#393,#394),(#395,#396,#397,#398,#399,#400,#401,#402),(#403,#404,#405,#406,
#407,#408,#409,#410),(#411,#412,#413,#414,#415,#416,#417,#418),(#419,#420,#421,#422,#423,#424,
#425,#426),(#427,#428,#429,#430,#431,#432,#433,#434),(#435,#436,#437,#438,#439,#440,#441,#442),
(#443,#444,#445,#446,#447,#448,#449,#450),(#451,#452,#453,#454,#455,#456,#457,#458)),
.UNSPECIFIED.,.F.,.F.,.F.,(4,1,1,1,1,1,1,4),(4,1,1,1,1,4),(0.,0.161829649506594,
0.33728011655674,0.430707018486,0.637101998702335,0.783997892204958,0.789371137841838,1.),(0.,
0.291685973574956,0.310378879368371,0.65187108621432,0.695528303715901,1.),.UNSPECIFIED.);
#460=CARTESIAN_POINT('',(0.,-375.,100.));
#461=CARTESIAN_POINT('',(0.,-373.754692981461,100.080415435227));
#462=CARTESIAN_POINT('',(0.,-372.510652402,100.180648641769));
#463=CARTESIAN_POINT('',(0.,-370.026977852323,100.420938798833));
#464=CARTESIAN_POINT('',(0.,-368.787342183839,100.560978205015));
#465=CARTESIAN_POINT('',(0.,-366.313659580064,100.881086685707));
#466=CARTESIAN_POINT('',(0.,-365.079610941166,101.061142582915));
#467=CARTESIAN_POINT('',(0.,-362.618261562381,101.461235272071));
#468=CARTESIAN_POINT('',(0.,-361.390959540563,101.681264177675));
#469=CARTESIAN_POINT('',(0.,-358.944229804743,102.161064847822));
#470=CARTESIAN_POINT('',(0.,-357.724801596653,102.42083409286));
#471=CARTESIAN_POINT('',(0.,-355.313339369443,102.975426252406));
#472=CARTESIAN_POINT('',(0.,-354.121169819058,103.26966026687));
#473=CARTESIAN_POINT('',(0.,-351.746642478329,103.895579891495));
#474=CARTESIAN_POINT('',(0.,-350.564285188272,104.227267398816));
#475=CARTESIAN_POINT('',(0.,-348.210367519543,104.927251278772));
#476=CARTESIAN_POINT('',(0.,-347.038807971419,105.295550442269));
#477=CARTESIAN_POINT('',(0.,-344.707403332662,106.067727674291));
#478=CARTESIAN_POINT('',(0.,-343.547558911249,106.471607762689));
#479=CARTESIAN_POINT('',(0.,-341.240466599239,107.313718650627));
#480=CARTESIAN_POINT('',(0.,-340.093218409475,107.751948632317));
#481=CARTESIAN_POINT('',(0.,-337.295884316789,108.867193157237));
#482=CARTESIAN_POINT('',(0.,-335.653082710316,109.562553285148));
#483=CARTESIAN_POINT('',(0.,-332.396383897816,111.01871471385));
#484=CARTESIAN_POINT('',(0.,-330.782493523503,111.779531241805));
#485=CARTESIAN_POINT('',(0.,-327.584140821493,113.362010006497));
#486=CARTESIAN_POINT('',(0.,-325.999689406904,114.183694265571));
#487=CARTESIAN_POINT('',(0.,-322.860614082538,115.882943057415));
#488=CARTESIAN_POINT('',(0.,-321.305997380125,116.760520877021));
#489=CARTESIAN_POINT('',(0.,-318.226816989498,118.566295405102));
#490=CARTESIAN_POINT('',(0.,-316.702248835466,119.4944845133));
#491=CARTESIAN_POINT('',(0.,-313.671526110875,121.403365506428));
#492=CARTESIAN_POINT('',(0.,-312.165574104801,122.384378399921));
#493=CARTESIAN_POINT('',(0.,-309.182210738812,124.387775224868));
#494=CARTESIAN_POINT('',(0.,-307.704790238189,125.410145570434));
#495=CARTESIAN_POINT('',(0.,-304.776492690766,127.491862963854));
#496=CARTESIAN_POINT('',(0.,-303.32561315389,128.551206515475));
#497=CARTESIAN_POINT('',(0.,-300.448445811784,130.702544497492));
#498=CARTESIAN_POINT('',(0.,-299.022156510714,131.794536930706));
#499=CARTESIAN_POINT('',(0.,-296.192279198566,134.006909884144));
#500=CARTESIAN_POINT('',(0.,-294.788686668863,135.127284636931));
#501=CARTESIAN_POINT('',(0.,-291.018856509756,138.191665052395));
#502=CARTESIAN_POINT('',(0.,-288.671818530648,140.159294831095));
#503=CARTESIAN_POINT('',(0.,-284.024752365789,144.148788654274));
#504=CARTESIAN_POINT('',(0.,-281.72472232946,146.170650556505));
#505=CARTESIAN_POINT('',(0.,-277.158401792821,150.253646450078));
#506=CARTESIAN_POINT('',(0.,-274.892123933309,152.31479452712));
#507=CARTESIAN_POINT('',(0.,-270.380674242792,156.461947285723));
#508=CARTESIAN_POINT('',(0.,-268.135512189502,158.54796255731));
#509=CARTESIAN_POINT('',(0.,-263.65398014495,162.73081755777));
#510=CARTESIAN_POINT('',(0.,-261.417613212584,164.827660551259));
#511=CARTESIAN_POINT('',(0.,-256.942613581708,169.01723058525));
#512=CARTESIAN_POINT('',(0.,-254.703982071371,171.10995888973));
#513=CARTESIAN_POINT('',(0.,-250.211535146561,175.278025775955));
#514=CARTESIAN_POINT('',(0.,-247.957723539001,177.353368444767));
#515=CARTESIAN_POINT('',(0.,-243.422876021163,181.472095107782));
#516=CARTESIAN_POINT('',(0.,-241.141853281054,183.515493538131));
#517=CARTESIAN_POINT('',(0.,-236.540167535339,187.555297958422));
#518=CARTESIAN_POINT('',(0.,-234.219522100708,189.551723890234));
#519=CARTESIAN_POINT('',(0.,-229.525486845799,193.481989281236));
#520=CARTESIAN_POINT('',(0.,-227.152097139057,195.415828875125));
#521=CARTESIAN_POINT('',(0.,-223.47179807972,198.312549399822));
#522=CARTESIAN_POINT('',(0.,-222.187857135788,199.30464490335));
#523=CARTESIAN_POINT('',(0.,-219.60016290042,201.263224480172));
#524=CARTESIAN_POINT('',(0.,-218.296405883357,202.229703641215));
#525=CARTESIAN_POINT('',(0.,-215.667839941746,204.133717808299));
#526=CARTESIAN_POINT('',(0.,-214.343030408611,205.071251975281));
#527=CARTESIAN_POINT('',(0.,-211.671088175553,206.914024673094));
#528=CARTESIAN_POINT('',(0.,-210.323955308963,207.819262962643));
#529=CARTESIAN_POINT('',(0.,-207.606085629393,209.594072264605));
#530=CARTESIAN_POINT('',(0.,-206.235345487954,210.463638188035));
#531=CARTESIAN_POINT('',(0.,-203.477263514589,212.158622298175));
#532=CARTESIAN_POINT('',(0.,-202.090055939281,212.984258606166));
#533=CARTESIAN_POINT('',(0.,-199.29092871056,214.592950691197));
#534=CARTESIAN_POINT('',(0.,-197.879006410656,215.376001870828));
#535=CARTESIAN_POINT('',(0.,-195.030427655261,216.895673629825));
#536=CARTESIAN_POINT('',(0.,-193.593772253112,217.632296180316));
#537=CARTESIAN_POINT('',(0.,-190.695807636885,219.055442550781));
#538=CARTESIAN_POINT('',(0.,-189.234498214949,219.741965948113));
#539=CARTESIAN_POINT('',(0.,-186.287394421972,221.061468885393));
#540=CARTESIAN_POINT('',(0.,-184.801593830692,221.694434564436));
#541=CARTESIAN_POINT('',(0.,-182.033423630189,222.811742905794));
#542=CARTESIAN_POINT('',(0.,-180.754278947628,223.304084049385));
#543=CARTESIAN_POINT('',(0.,-178.179854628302,224.245788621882));
#544=CARTESIAN_POINT('',(0.,-176.884570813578,224.695140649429));
#545=CARTESIAN_POINT('',(0.,-174.279341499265,225.548845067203));
#546=CARTESIAN_POINT('',(0.,-172.969396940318,225.953200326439));
#547=CARTESIAN_POINT('',(0.,-170.336124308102,226.714489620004));
#548=CARTESIAN_POINT('',(0.,-169.01279997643,227.071436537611));
#549=CARTESIAN_POINT('',(0.,-167.018874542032,227.569847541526));
#550=CARTESIAN_POINT('',(0.,-166.352845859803,227.729794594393));
#551=CARTESIAN_POINT('',(0.,-165.017900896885,228.037182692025));
#552=CARTESIAN_POINT('',(0.,-164.348984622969,228.184623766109));
#553=CARTESIAN_POINT('',(0.,-163.008708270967,228.466757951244));
#554=CARTESIAN_POINT('',(0.,-162.33734910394,228.601455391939));
#555=CARTESIAN_POINT('',(0.,-160.992185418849,228.858027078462));
#556=CARTESIAN_POINT('',(0.,-160.318380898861,228.979901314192));
#557=CARTESIAN_POINT('',(0.,-158.965931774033,229.21165761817));
#558=CARTESIAN_POINT('',(0.,-158.287278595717,229.321489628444));
#559=CARTESIAN_POINT('',(0.,-156.928116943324,229.528946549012));
#560=CARTESIAN_POINT('',(0.,-156.247608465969,229.62657143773));
#561=CARTESIAN_POINT('',(0.,-154.203443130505,229.901706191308));
#562=CARTESIAN_POINT('',(0.,-152.837358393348,230.06144006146));
#563=CARTESIAN_POINT('',(0.,-150.100212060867,230.336372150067));
#564=CARTESIAN_POINT('',(0.,-148.729148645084,230.451551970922));
#565=CARTESIAN_POINT('',(0.,-145.983595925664,230.640089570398));
#566=CARTESIAN_POINT('',(0.,-144.609105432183,230.713429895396));
#567=CARTESIAN_POINT('',(0.,-141.858288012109,230.820887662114));
#568=CARTESIAN_POINT('',(0.,-140.481960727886,230.854995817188));
#569=CARTESIAN_POINT('',(0.,-137.729073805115,230.886486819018));
#570=CARTESIAN_POINT('',(0.,-136.352514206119,230.88387352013));
#571=CARTESIAN_POINT('',(0.,-132.347250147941,230.826361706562));
#572=CARTESIAN_POINT('',(0.,-129.719116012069,230.726044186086));
#573=CARTESIAN_POINT('',(0.,-124.470064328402,230.415569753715));
#574=CARTESIAN_POINT('',(0.,-121.849145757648,230.205429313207));
#575=CARTESIAN_POINT('',(0.,-116.615647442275,229.688489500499));
#576=CARTESIAN_POINT('',(0.,-114.00307253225,229.381641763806));
#577=CARTESIAN_POINT('',(0.,-108.787837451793,228.682695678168));
#578=CARTESIAN_POINT('',(0.,-106.185184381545,228.290544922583));
#579=CARTESIAN_POINT('',(0.,-100.991506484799,227.431021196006));
#580=CARTESIAN_POINT('',(0.,-98.4004859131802,226.963622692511));
#581=CARTESIAN_POINT('',(0.,-93.2319544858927,225.962554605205));
#582=CARTESIAN_POINT('',(0.,-90.6544407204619,225.428899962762));
#583=CARTESIAN_POINT('',(0.,-85.4943831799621,224.298912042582));
#584=CARTESIAN_POINT('',(0.,-82.9119298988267,223.702167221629));
#585=CARTESIAN_POINT('',(0.,-77.761631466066,222.456329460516));
#586=CARTESIAN_POINT('',(0.,-75.1937773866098,221.807273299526));
#587=CARTESIAN_POINT('',(0.,-70.0713342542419,220.462654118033));
#588=CARTESIAN_POINT('',(0.,-67.5167406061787,219.767108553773));
#589=CARTESIAN_POINT('',(0.,-62.4196682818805,218.334673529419));
#590=CARTESIAN_POINT('',(0.,-59.877187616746,217.597791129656));
#591=CARTESIAN_POINT('',(0.,-54.8033466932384,216.087298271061));
#592=CARTESIAN_POINT('',(0.,-52.2719857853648,215.313689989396));
#593=CARTESIAN_POINT('',(0.,-47.2195130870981,213.733916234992));
#594=CARTESIAN_POINT('',(0.,-44.6984011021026,212.927751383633));
#595=CARTESIAN_POINT('',(0.,-40.1184237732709,211.434305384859));
#596=CARTESIAN_POINT('',(0.,-38.0580181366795,210.751737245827));
#597=CARTESIAN_POINT('',(0.,-33.9430648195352,209.369152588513));
#598=CARTESIAN_POINT('',(0.,-31.8885171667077,208.6691359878));
#599=CARTESIAN_POINT('',(0.,-25.7327115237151,206.545537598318));
#600=CARTESIAN_POINT('',(0.,-21.639541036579,205.098489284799));
#601=CARTESIAN_POINT('',(0.,-13.4707450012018,202.154685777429));
#602=CARTESIAN_POINT('',(0.,-9.39512119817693,200.657925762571));
#603=CARTESIAN_POINT('',(0.,-1.25803868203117,197.626293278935));
#604=CARTESIAN_POINT('',(0.,2.80341982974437,196.091420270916));
#605=CARTESIAN_POINT('',(0.,10.9047980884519,192.998195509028));
#606=CARTESIAN_POINT('',(0.,14.9447463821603,191.439918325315));
#607=CARTESIAN_POINT('',(0.,23.0173755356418,188.305591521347));
#608=CARTESIAN_POINT('',(0.,27.0500569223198,186.729543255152));
#609=CARTESIAN_POINT('',(0.,35.1119090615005,183.568980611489));
#610=CARTESIAN_POINT('',(0.,39.1410799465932,181.98446657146));
#611=CARTESIAN_POINT('',(0.,45.1852435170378,179.608839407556));
#612=CARTESIAN_POINT('',(0.,47.2000142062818,178.817161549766));
#613=CARTESIAN_POINT('',(0.,51.2302618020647,177.235606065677));
#614=CARTESIAN_POINT('',(0.,53.2457387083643,176.445728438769));
#615=CARTESIAN_POINT('',(0.,57.151099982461,174.918943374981));
#616=CARTESIAN_POINT('',(0.,59.0409042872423,174.181831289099));
#617=CARTESIAN_POINT('',(0.,62.8222355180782,172.712000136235));
#618=CARTESIAN_POINT('',(0.,64.7137624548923,171.979281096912));
#619=CARTESIAN_POINT('',(0.,68.4991614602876,170.519827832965));
#620=CARTESIAN_POINT('',(0.,70.393033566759,169.793093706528));
#621=CARTESIAN_POINT('',(0.,74.1838664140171,168.347518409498));
#622=CARTESIAN_POINT('',(0.,76.080827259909,167.628677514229));
#623=CARTESIAN_POINT('',(0.,79.8786636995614,166.201015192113));
#624=CARTESIAN_POINT('',(0.,81.7795395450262,165.492194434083));
#625=CARTESIAN_POINT('',(0.,85.5860642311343,164.086782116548));
#626=CARTESIAN_POINT('',(0.,87.4917136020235,163.390191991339));
#627=CARTESIAN_POINT('',(0.,91.3030320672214,162.01356078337));
#628=CARTESIAN_POINT('',(0.,93.2086865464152,161.333479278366));
#629=CARTESIAN_POINT('',(0.,97.0260253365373,159.990209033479));
#630=CARTESIAN_POINT('',(0.,98.9377098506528,159.327020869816));
#631=CARTESIAN_POINT('',(0.,101.81012378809,158.346706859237));
#632=CARTESIAN_POINT('',(0.,102.768389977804,158.022353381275));
#633=CARTESIAN_POINT('',(0.,104.686640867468,157.378762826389));
#634=CARTESIAN_POINT('',(0.,105.646625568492,157.059525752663));
#635=CARTESIAN_POINT('',(0.,107.568283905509,156.426451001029));
#636=CARTESIAN_POINT('',(0.,108.529957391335,156.112612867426));
#637=CARTESIAN_POINT('',(0.,110.455180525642,155.490743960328));
#638=CARTESIAN_POINT('',(0.,111.418730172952,155.182713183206));
#639=CARTESIAN_POINT('',(0.,113.347846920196,154.573245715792));
#640=CARTESIAN_POINT('',(0.,114.313413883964,154.271808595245));
#641=CARTESIAN_POINT('',(0.,116.246803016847,153.676263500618));
#642=CARTESIAN_POINT('',(0.,117.214625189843,153.382155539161));
#643=CARTESIAN_POINT('',(0.,120.121904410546,152.511969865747));
#644=CARTESIAN_POINT('',(0.,122.065045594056,151.948071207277));
#645=CARTESIAN_POINT('',(0.,124.991729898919,151.130973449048));
#646=CARTESIAN_POINT('',(0.,125.971140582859,150.862922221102));
#647=CARTESIAN_POINT('',(0.,127.93292787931,150.337859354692));
#648=CARTESIAN_POINT('',(0.,128.915304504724,150.080847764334));
#649=CARTESIAN_POINT('',(0.,130.883075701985,149.579012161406));
#650=CARTESIAN_POINT('',(0.,131.868469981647,149.334187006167));
#651=CARTESIAN_POINT('',(0.,133.348911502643,148.977030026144));
#652=CARTESIAN_POINT('',(0.,133.842748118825,148.859665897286));
#653=CARTESIAN_POINT('',(0.,134.831246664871,148.628462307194));
#654=CARTESIAN_POINT('',(0.,135.325908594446,148.514622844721));
#655=CARTESIAN_POINT('',(0.,136.315994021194,148.29066048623));
#656=CARTESIAN_POINT('',(0.,136.811417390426,148.18053702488));
#657=CARTESIAN_POINT('',(0.,137.803115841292,147.964193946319));
#658=CARTESIAN_POINT('',(0.,138.299390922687,147.857974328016));
#659=CARTESIAN_POINT('',(0.,139.292689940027,147.649417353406));
#660=CARTESIAN_POINT('',(0.,139.78971377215,147.54707950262));
#661=CARTESIAN_POINT('',(0.,140.78452723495,147.346200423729));
#662=CARTESIAN_POINT('',(0.,141.282316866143,147.247659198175));
#663=CARTESIAN_POINT('',(0.,142.778908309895,146.957209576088));
#664=CARTESIAN_POINT('',(0.,143.778806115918,146.77092108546));
#665=CARTESIAN_POINT('',(0.,145.78125144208,146.412607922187));
#666=CARTESIAN_POINT('',(0.,146.783799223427,146.240584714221));
#667=CARTESIAN_POINT('',(0.,148.791253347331,145.909987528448));
#668=CARTESIAN_POINT('',(0.,149.796160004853,145.751415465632));
#669=CARTESIAN_POINT('',(0.,151.808018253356,145.446807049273));
#670=CARTESIAN_POINT('',(0.,152.814970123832,145.300772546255));
#671=CARTESIAN_POINT('',(0.,154.830594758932,145.020238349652));
#672=CARTESIAN_POINT('',(0.,155.839267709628,144.885739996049));
#673=CARTESIAN_POINT('',(0.,157.857996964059,144.627205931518));
#674=CARTESIAN_POINT('',(0.,158.868053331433,144.503170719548));
#675=CARTESIAN_POINT('',(0.,161.896361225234,144.145483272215));
#676=CARTESIAN_POINT('',(0.,163.916261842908,143.925768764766));
#677=CARTESIAN_POINT('',(0.,167.958914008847,143.514176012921));
#678=CARTESIAN_POINT('',(0.,169.981665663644,143.322298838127));
#679=CARTESIAN_POINT('',(0.,174.028748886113,142.957091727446));
#680=CARTESIAN_POINT('',(0.,176.05308039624,142.783761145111));
#681=CARTESIAN_POINT('',(0.,179.090170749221,142.531187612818));
#682=CARTESIAN_POINT('',(0.,180.10262717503,142.448233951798));
#683=CARTESIAN_POINT('',(0.,182.127663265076,142.283842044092));
#684=CARTESIAN_POINT('',(0.,183.140242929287,142.202403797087));
#685=CARTESIAN_POINT('',(0.,186.178204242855,141.959070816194));
#686=CARTESIAN_POINT('',(0.,188.203664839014,141.79816951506));
#687=CARTESIAN_POINT('',(0.,192.254347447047,141.473338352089));
#688=CARTESIAN_POINT('',(0.,194.279569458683,141.309408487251));
#689=CARTESIAN_POINT('',(0.,198.329449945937,140.974276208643));
#690=CARTESIAN_POINT('',(0.,200.354108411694,140.803073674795));
#691=CARTESIAN_POINT('',(0.,204.402530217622,140.450370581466));
#692=CARTESIAN_POINT('',(0.,206.426293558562,140.268870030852));
#693=CARTESIAN_POINT('',(0.,210.472938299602,139.893516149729));
#694=CARTESIAN_POINT('',(0.,212.49581955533,139.699661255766));
#695=CARTESIAN_POINT('',(0.,216.540227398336,139.29833234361));
#696=CARTESIAN_POINT('',(0.,218.561753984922,139.090858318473));
#697=CARTESIAN_POINT('',(0.,224.625505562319,138.446613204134));
#698=CARTESIAN_POINT('',(0.,228.665465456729,137.988150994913));
#699=CARTESIAN_POINT('',(0.,234.707971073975,137.255474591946));
#700=CARTESIAN_POINT('',(0.,236.713370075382,137.004554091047));
#701=CARTESIAN_POINT('',(0.,240.722134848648,136.486911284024));
#702=CARTESIAN_POINT('',(0.,242.725500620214,136.220188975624));
#703=CARTESIAN_POINT('',(0.,246.73111521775,135.670098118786));
#704=CARTESIAN_POINT('',(0.,248.733362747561,135.38672012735));
#705=CARTESIAN_POINT('',(0.,252.735321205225,134.802571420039));
#706=CARTESIAN_POINT('',(0.,254.73503213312,134.501800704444));
#707=CARTESIAN_POINT('',(0.,258.731864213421,133.881728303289));
#708=CARTESIAN_POINT('',(0.,260.728984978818,133.562424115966));
#709=CARTESIAN_POINT('',(0.,264.719966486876,132.904053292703));
#710=CARTESIAN_POINT('',(0.,266.713827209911,132.564986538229));
#711=CARTESIAN_POINT('',(0.,272.689152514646,131.516161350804));
#712=CARTESIAN_POINT('',(0.,276.66514771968,130.774656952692));
#713=CARTESIAN_POINT('',(0.,282.6141093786,129.590583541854));
#714=CARTESIAN_POINT('',(0.,284.594292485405,129.183989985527));
#715=CARTESIAN_POINT('',(0.,288.549329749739,128.34555938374));
#716=CARTESIAN_POINT('',(0.,290.524183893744,127.91372227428));
#717=CARTESIAN_POINT('',(0.,294.467417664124,127.023837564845));
#718=CARTESIAN_POINT('',(-1.01448654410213E-13,296.435798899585,126.565797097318));
#719=CARTESIAN_POINT('',(0.,300.366024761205,125.622553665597));
#720=CARTESIAN_POINT('',(0.,302.327869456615,125.137350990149));
#721=CARTESIAN_POINT('',(0.,306.289869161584,124.127629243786));
#722=CARTESIAN_POINT('',(0.,308.28985847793,123.602459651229));
#723=CARTESIAN_POINT('',(-1.0383389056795E-13,312.281694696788,122.522796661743));
#724=CARTESIAN_POINT('',(-1.02594547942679E-13,314.273542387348,121.968306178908));
#725=CARTESIAN_POINT('',(-1.02059889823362E-13,318.248693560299,120.829960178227));
#726=CARTESIAN_POINT('',(-1.02764452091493E-13,320.231997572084,120.246106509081));
#727=CARTESIAN_POINT('',(-1.03651426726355E-13,324.189739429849,119.049257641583));
#728=CARTESIAN_POINT('',(-1.03833851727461E-13,326.164177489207,118.436263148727));
#729=CARTESIAN_POINT('',(-1.04335646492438E-13,330.103937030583,117.181590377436));
#730=CARTESIAN_POINT('',(-1.04655017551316E-13,332.069258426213,116.539911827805));
#731=CARTESIAN_POINT('',(-1.05260009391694E-13,335.990594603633,115.228527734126));
#732=CARTESIAN_POINT('',(-1.05545629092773E-13,337.946609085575,114.558821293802));
#733=CARTESIAN_POINT('',(-1.06110708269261E-13,341.877307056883,113.18235449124));
#734=CARTESIAN_POINT('',(-1.06390019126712E-13,343.851851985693,112.475198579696));
#735=CARTESIAN_POINT('',(-1.07016015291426E-13,347.791147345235,111.033865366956));
#736=CARTESIAN_POINT('',(-1.07362703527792E-13,349.75589734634,110.299686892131));
#737=CARTESIAN_POINT('',(-1.07788374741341E-13,353.675601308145,108.805367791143));
#738=CARTESIAN_POINT('',(-1.07867345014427E-13,355.630554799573,108.045225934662));
#739=CARTESIAN_POINT('',(-1.09020097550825E-13,359.530690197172,106.500103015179));
#740=CARTESIAN_POINT('',(-1.10093912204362E-13,361.475871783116,105.715121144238));
#741=CARTESIAN_POINT('',(-1.08521196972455E-13,365.356501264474,104.121481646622));
#742=CARTESIAN_POINT('',(-1.05874673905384E-13,367.291949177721,103.31282406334));
#743=CARTESIAN_POINT('',(-1.14459242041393E-13,371.153166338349,101.673011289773));
#744=CARTESIAN_POINT('',(-1.25689562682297E-13,373.078936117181,100.841857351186));
#745=CARTESIAN_POINT('',(-1.52655665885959E-13,375.,100.));
#746=B_SPLINE_CURVE_WITH_KNOTS('',3,(#460,#461,#462,#463,#464,#465,#466,#467,#468,#469,#470,
#471,#472,#473,#474,#475,#476,#477,#478,#479,#480,#481,#482,#483,#484,#485,#486,#487,#488,#489,
#490,#491,#492,#493,#494,#495,#496,#497,#498,#499,#500,#501,#502,#503,#504,#505,#506,#507,#508,
#509,#510,#511,#512,#513,#514,#515,#516,#517,#518,#519,#520,#521,#522,#523,#524,#525,#526,#527,
#528,#529,#530,#531,#532,#533,#534,#535,#536,#537,#538,#539,#540,#541,#542,#543,#544,#545,#546,
#547,#548,#549,#550,#551,#552,#553,#554,#555,#556,#557,#558,#559,#560,#561,#562,#563,#564,#565,
#566,#567,#568,#569,#570,#571,#572,#573,#574,#575,#576,#577,#578,#579,#580,#581,#582,#583,#584,
#585,#586,#587,#588,#589,#590,#591,#592,#593,#594,#595,#596,#597,#598,#599,#600,#601,#602,#603,
#604,#605,#606,#607,#608,#609,#610,#611,#612,#613,#614,#615,#616,#617,#618,#619,#620,#621,#622,
#623,#624,#625,#626,#627,#628,#629,#630,#631,#632,#633,#634,#635,#636,#637,#638,#639,#640,#641,
#642,#643,#644,#645,#646,#647,#648,#649,#650,#651,#652,#653,#654,#655,#656,#657,#658,#659,#660,
#661,#662,#663,#664,#665,#666,#667,#668,#669,#670,#671,#672,#673,#674,#675,#676,#677,#678,#679,
#680,#681,#682,#683,#684,#685,#686,#687,#688,#689,#690,#691,#692,#693,#694,#695,#696,#697,#698,
#699,#700,#701,#702,#703,#704,#705,#706,#707,#708,#709,#710,#711,#712,#713,#714,#715,#716,#717,
#718,#719,#720,#721,#722,#723,#724,#725,#726,#727,#728,#729,#730,#731,#732,#733,#734,#735,#736,
#737,#738,#739,#740,#741,#742,#743,#744,#745),.UNSPECIFIED.,.F.,.F.,(4,2,2,2,2,2,2,2,2,2,2,2,2,
2,2,2,2,2,2,2,2,2,2,2,2,2,2,2,2,2,2,2,2,2,2,2,2,2,2,2,2,2,2,2,2,2,2,2,2,2,2,2,2,2,2,2,2,2,2,2,2,
2,2,2,2,2,2,2,2,2,2,2,2,2,2,2,2,2,2,2,2,2,2,2,2,2,2,2,2,2,2,2,2,2,2,2,2,2,2,2,2,2,2,2,2,2,2,2,2,
2,2,2,2,2,2,2,2,2,2,2,2,2,2,2,2,2,2,2,2,2,2,2,2,2,2,2,2,2,2,2,2,2,4),(0.,3.74356419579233,
7.48548099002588,11.2261674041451,14.9661166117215,18.7058288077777,22.3890399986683,
26.0724378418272,29.7561166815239,33.4400047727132,37.1238051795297,42.4739204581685,
47.8252837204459,53.1785926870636,58.5331790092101,63.8869634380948,69.2780849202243,
74.6674495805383,80.0563059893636,85.4448334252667,90.8322745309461,100.019153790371,
109.205670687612,118.395545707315,127.589485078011,136.78638046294,145.979771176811,
155.170936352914,164.35782025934,173.540730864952,182.723621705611,187.591087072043,
192.45947917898,197.32801227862,202.196581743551,207.065843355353,211.908096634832,
216.750871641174,221.593440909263,226.436051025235,231.27991061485,235.391060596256,
239.503297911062,243.615272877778,247.726128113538,249.780924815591,251.835716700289,
253.889807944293,255.943900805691,258.00623210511,260.068567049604,264.193881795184,
268.320898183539,272.449634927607,276.579348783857,280.708629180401,288.595861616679,
296.481911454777,304.371911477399,312.266772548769,320.164318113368,328.060085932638,
336.01097281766,343.95631754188,351.898695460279,359.839720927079,367.780276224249,
375.720680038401,382.232166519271,388.74368376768,401.767508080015,414.792599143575,
427.817874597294,440.807986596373,453.797115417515,466.785730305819,473.279919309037,
479.774106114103,485.85951538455,491.94496292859,498.030510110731,504.116268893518,
510.202431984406,516.28930410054,522.35935093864,528.429604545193,531.464607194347,
534.499611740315,537.534358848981,540.569104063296,543.603650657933,546.638202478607,
552.707710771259,555.753947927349,558.800198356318,561.846162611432,563.368925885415,
564.891688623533,566.41421864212,567.936748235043,569.45908322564,570.981419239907,
574.032608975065,577.084111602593,580.136047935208,583.188433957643,586.241174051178,
589.294059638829,595.389203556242,601.484581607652,607.579747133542,610.627294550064,
613.674841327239,619.770366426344,625.865897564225,631.961529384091,638.057155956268,
644.153555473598,650.249958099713,662.447091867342,668.510151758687,674.573212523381,
680.639744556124,686.706276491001,692.773629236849,698.841018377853,710.973406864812,
717.037763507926,723.102135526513,729.164864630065,735.227529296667,741.430680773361,
747.633216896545,753.83536299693,760.037359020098,766.239413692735,772.441666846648,
778.733527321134,785.025661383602,791.318094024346,797.610731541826,803.903357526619,
810.195634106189),.UNSPECIFIED.);
#747=CARTESIAN_POINT('',(0.,-375.,100.));
#748=VERTEX_POINT('',#747);
#749=CARTESIAN_POINT('',(-1.11022302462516E-13,375.,100.));
#750=VERTEX_POINT('',#749);
#751=EDGE_CURVE('E11',#748,#750,#746,.T.);
#752=CARTESIAN_POINT('',(-750.,-375.,100.));
#753=CARTESIAN_POINT('',(-644.685568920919,-375.,100.));
#754=CARTESIAN_POINT('',(-536.684515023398,-375.,100.));
#755=CARTESIAN_POINT('',(-355.235514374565,-375.,100.));
#756=CARTESIAN_POINT('',(-175.903454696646,-375.,100.));
#757=CARTESIAN_POINT('',(47.4554331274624,-375.,100.));
#758=CARTESIAN_POINT('',(285.091607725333,-375.,100.));
#759=CARTESIAN_POINT('',(500.445116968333,-375.,100.));
#760=CARTESIAN_POINT('',(669.085175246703,-375.,100.));
#761=CARTESIAN_POINT('',(750.,-375.,100.));
#762=B_SPLINE_CURVE_WITH_KNOTS('',3,(#752,#753,#754,#755,#756,#757,#758,#759,#760,#761),
.UNSPECIFIED.,.F.,.F.,(4,1,1,1,1,1,1,4),(0.,0.210628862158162,0.216002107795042,
0.362898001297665,0.569292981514,0.66271988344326,0.838170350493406,1.),.UNSPECIFIED.);
#763=EDGE_CURVE('E97',#748,#320,#762,.T.);
#764=CARTESIAN_POINT('',(750.,375.,100.));
#765=CARTESIAN_POINT('',(669.085175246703,375.,100.));
#766=CARTESIAN_POINT('',(500.445116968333,375.,100.));
#767=CARTESIAN_POINT('',(285.091607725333,375.,100.));
#768=CARTESIAN_POINT('',(47.4554331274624,375.,100.));
#769=CARTESIAN_POINT('',(-175.903454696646,375.,100.));
#770=CARTESIAN_POINT('',(-355.235514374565,375.,100.));
#771=CARTESIAN_POINT('',(-536.684515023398,375.,100.));
#772=CARTESIAN_POINT('',(-644.685568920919,375.,100.));
#773=CARTESIAN_POINT('',(-750.,375.,100.));
#774=B_SPLINE_CURVE_WITH_KNOTS('',3,(#764,#765,#766,#767,#768,#769,#770,#771,#772,#773),
.UNSPECIFIED.,.F.,.F.,(4,1,1,1,1,1,1,4),(0.,0.161829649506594,0.33728011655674,0.430707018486,
0.637101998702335,0.783997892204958,0.789371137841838,1.),.UNSPECIFIED.);
#775=EDGE_CURVE('E94',#318,#750,#774,.T.);
#776=ORIENTED_EDGE('',*,*,#751,.F.);
#777=ORIENTED_EDGE('',*,*,#763,.T.);
#778=ORIENTED_EDGE('',*,*,#321,.F.);
#779=ORIENTED_EDGE('',*,*,#775,.T.);
#780=EDGE_LOOP('',(#776,#777,#778,#779));
#781=FACE_BOUND('',#780,.T.);
#782=ADVANCED_FACE('F110',(#781),#459,.F.);
#783=CARTESIAN_POINT('',(-750.,375.,253.111113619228));
#784=DIRECTION('',(0.,-1.,0.));
#785=DIRECTION('',(0.,0.,-1.));
#786=AXIS2_PLACEMENT_3D('',#783,#784,#785);
#787=PLANE('',#786);
#788=DIRECTION('',(0.,0.,-1.));
#789=VECTOR('',#788,1.);
#790=CARTESIAN_POINT('',(-1.11022302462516E-13,375.,253.120113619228));
#791=LINE('',#790,#789);
#792=EDGE_CURVE('E154',#750,#366,#791,.T.);
#793=ORIENTED_EDGE('',*,*,#792,.F.);
#794=ORIENTED_EDGE('',*,*,#775,.F.);
#795=ORIENTED_EDGE('',*,*,#343,.T.);
#796=ORIENTED_EDGE('',*,*,#373,.T.);
#797=EDGE_LOOP('',(#793,#794,#795,#796));
#798=FACE_BOUND('',#797,.T.);
#799=ADVANCED_FACE('F121',(#798),#787,.F.);
#800=CARTESIAN_POINT('',(-750.,-375.,253.111113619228));
#801=DIRECTION('',(0.,1.,0.));
#802=DIRECTION('',(0.,0.,1.));
#803=AXIS2_PLACEMENT_3D('',#800,#801,#802);
#804=PLANE('',#803);
#805=DIRECTION('',(0.,0.,-1.));
#806=VECTOR('',#805,1.);
#807=CARTESIAN_POINT('',(0.,-375.,253.120113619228));
#808=LINE('',#807,#806);
#809=EDGE_CURVE('E56',#748,#358,#808,.T.);
#810=ORIENTED_EDGE('',*,*,#809,.T.);
#811=ORIENTED_EDGE('',*,*,#359,.T.);
#812=ORIENTED_EDGE('',*,*,#329,.F.);
#813=ORIENTED_EDGE('',*,*,#763,.F.);
#814=EDGE_LOOP('',(#810,#811,#812,#813));
#815=FACE_BOUND('',#814,.T.);
#816=ADVANCED_FACE('F37',(#815),#804,.F.);
#817=CARTESIAN_POINT('',(-1.11022302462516E-13,375.,253.120113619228));
#818=DIRECTION('',(-1.,0.,0.));
#819=DIRECTION('',(0.,-1.,0.));
#820=AXIS2_PLACEMENT_3D('',#817,#818,#819);
#821=PLANE('',#820);
#822=ORIENTED_EDGE('',*,*,#751,.T.);
#823=ORIENTED_EDGE('',*,*,#792,.T.);
#824=ORIENTED_EDGE('',*,*,#367,.F.);
#825=ORIENTED_EDGE('',*,*,#809,.F.);
#826=EDGE_LOOP('',(#822,#823,#824,#825));
#827=FACE_BOUND('',#826,.T.);
#828=ADVANCED_FACE('F145',(#827),#821,.T.);
#829=CLOSED_SHELL('',(#347,#378,#782,#799,#816,#828));
#830=MANIFOLD_SOLID_BREP('B2',#829);
#831=ADVANCED_BREP_SHAPE_REPRESENTATION('',(#18,#830),#14);
#832=SHAPE_DEFINITION_REPRESENTATION(#9,#831);
ENDSEC;
END-ISO-10303-21;
